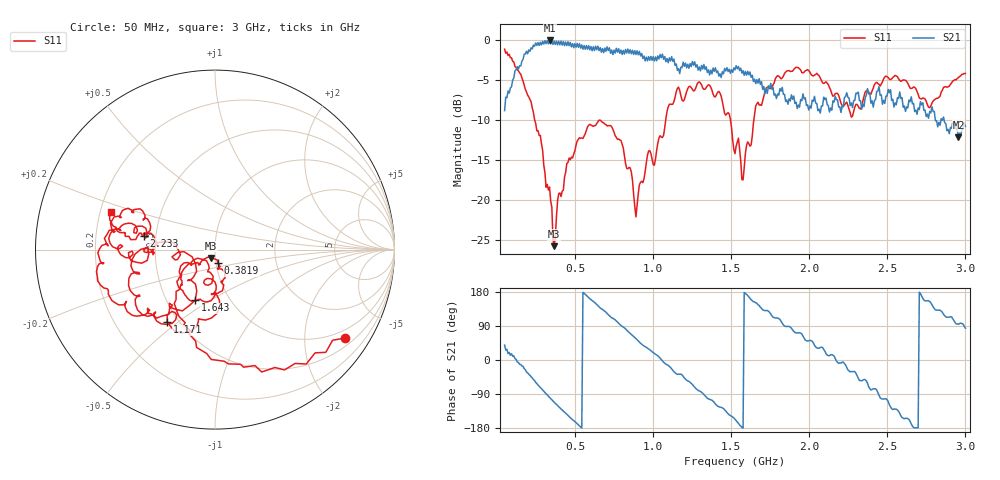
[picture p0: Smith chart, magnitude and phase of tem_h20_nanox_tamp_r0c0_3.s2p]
! nanovna_capture.py 2026-10-26T21:15:10+0900
! NanoVNA-F_V2 fw 0.6.0 SN 4A3639384505514B
! cal: load open short thru cal'ed  over 50000000-3000000000 Hz, 201 points
! points 401, avg 4
! TEM h=20, tampered Nano X, flat back down, 0 deg, centred, placement 3
# HZ S RI R 50
! S12 and S22 are not measured (written as 0)
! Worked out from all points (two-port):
!   401 points, 50 MHz to 3 GHz, reference 50 ohm
!   highest |S21| = -0.05 dB at 337.6 MHz (marker M1); lowest = -12.2 dB at 2.956 GHz (marker M2)
!   |S21| within 3 dB of the highest: 155.7 MHz to 1.14 GHz (984.7 MHz wide, 152 % of centre); 1.146764 GHz to 1.149313 GHz (2.549 MHz wide, 0.222 % of centre) (the widest 2 of 8)
!   lowest |S11| = -25.8 dB at 367.1 MHz (marker M3), VSWR 1.11, Z = 47.8 - j4.51 ohm
!   |S11| at or under -10 dB: 242.5 MHz to 1.081 GHz (839 MHz wide, 127 % of centre); 1.496 GHz to 1.646 GHz (149.4 MHz wide, 9.51 % of centre)
!   S12 and S22 are empty: the file has one direction only
!   S11 on the Smith chart (normalised r, x): 50 MHz: 0.73, -3.10; 381.9 MHz: 1.02, -0.16; 1.171 GHz: 0.43, -0.46; 1.643 GHz: 0.69, -0.43; 2.233 GHz: 0.43, +0.08; 3 GHz: 0.24, +0.16
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5e7  0.7256 -0.4926  0.2807 0.2281  0 0  0 0
1.09e8  0.2604 -0.6818  0.5695 0.1112  0 0  0 0
1.90125e8  -0.1361 -0.4533  0.7256 -0.446  0 0  0 0
3.37625e8  -0.0879 -0.0817  -0.1566 -0.9824  0 0  0 0
3.67125e8  -0.0203 -0.047  -0.3586 -0.9196  0 0  0 0
3.81875e8  0.018 -0.0764  -0.4518 -0.876  0 0  0 0
5.44125e8  -0.000491 -0.2438  -0.9326 -0.00782  0 0  0 0
7.80125e8  -0.1919 -0.1446  -0.1008 0.8768  0 0  0 0
8.9075e8  -0.0473 -0.0622  0.4461 0.6778  0 0  0 0
1.03825e9  -0.0071 -0.2437  0.7538 0.1103  0 0  0 0
1.171e9  -0.2669 -0.4043  0.487 -0.3787  0 0  0 0
1.325875e9  -0.4218 -0.2522  -0.0149 -0.7039  0 0  0 0
1.525e9  -0.1923 -0.0291  -0.5962 -0.2615  0 0  0 0
1.576625e9  -0.109 -0.0767  -0.6439 -0.00718  0 0  0 0
1.643e9  -0.1101 -0.2817  -0.4929 0.2446  0 0  0 0
1.827375e9  -0.497 -0.2982  -0.0604 0.5017  0 0  0 0
2.019125e9  -0.599 0.031  0.273 0.3196  0 0  0 0
2.233e9  -0.3948 0.0779  0.4312 -0.1  0 0  0 0
2.51325e9  -0.5597 0.1003  -0.2201 -0.4127  0 0  0 0
2.712375e9  -0.3911 0.1786  -0.4095 0.0384  0 0  0 0
2.95575e9  -0.5678 0.1315  -0.0188 0.2448  0 0  0 0
3e9  -0.5812 0.2092  0.0307 0.2862  0 0  0 0
